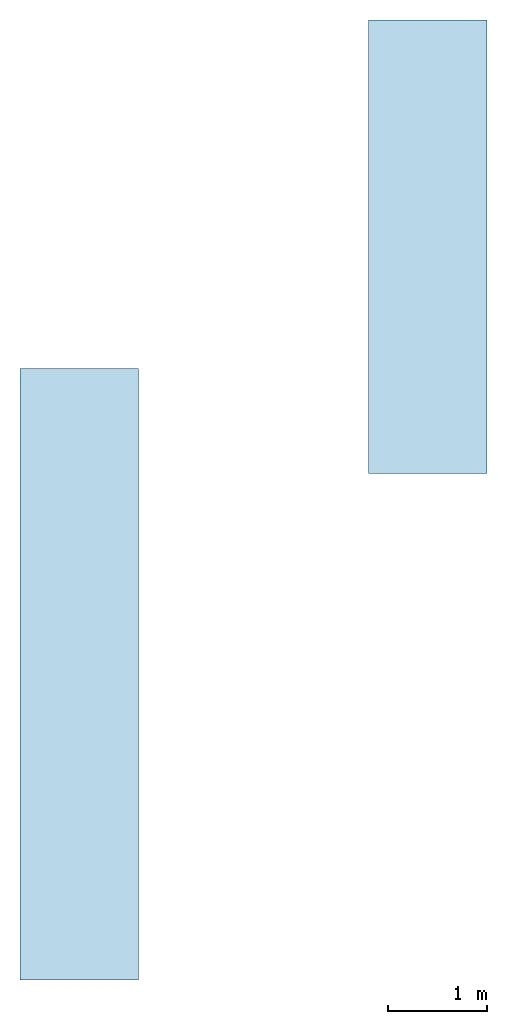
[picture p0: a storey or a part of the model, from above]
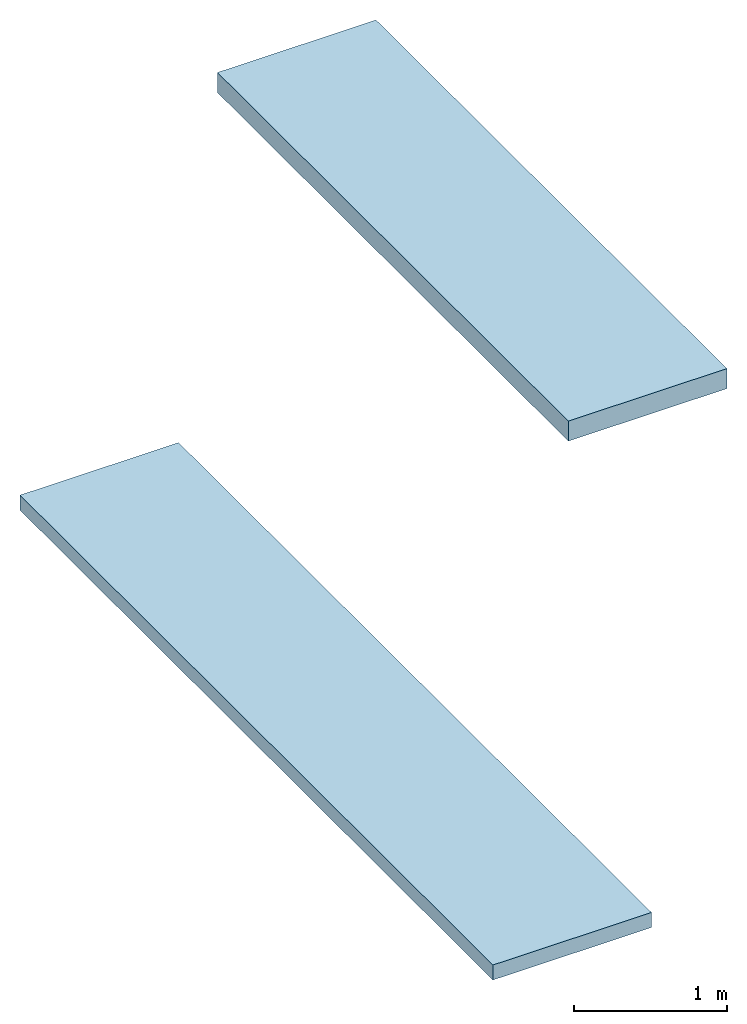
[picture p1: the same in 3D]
Properties of the parts of a building model (IFC2X3)

# File
Description: ViewDefinition [CoordinationView]
Time: 2023-01-18T09:51:32
Written by: The EXPRESS Data Manager Version 5.02.0100.07 : 28 Aug 2013
Made in: 21.1.70.21 - Exporter 21.1.70.21 - Alternate UI 21.1.70.21
Comment: STEP Physical File produced by: The EXPRESS Data Manager Version 5.02.0100.07 : 28 Aug 2013 * Module: EDMstepFileFactory/EDMstandAlone * Creation date: Wed Jan 18 09:51:32 2023 * Host: BIM-LT03 * Database: C:\Users\DONNEE~1\AppData\Local\Temp\6dfd9f73-01cb-4fe2-bb7c-203e315a706e\c1fa6ac3-a54c-4e9e-a12f-ee402be6c916\ifc * Database version: 5507 * Database creation date: Wed Jan 18 09:51:32 2023 * Schema: IFC2X3 * Model: DataRepository.ifc * Model creation date: Wed Jan 18 09:51:32 2023 * Header model: DataRepository.ifc_HeaderModel * Header model creation date: Wed Jan 18 09:51:32 2023 * EDMuser: sdai-user * EDMgroup: sdai-group * License ID and type: 5605 : Permanent license. Expiry date: * EDMstepFileFactory options: 020000

# IfcSite, Default
RefLatitude: 42, 24, 53, 508911; RefLongitude: -71, -15, -29, -58837; RefElevation: 0 mm
Pset_ProductRequirements - Category: Project Information

# IfcBuilding
Pset_BuildingCommon - NumberOfStoreys: 1
Pset_ProductRequirements - Category: Project Information

# IfcBuildingStorey: Level:Level 1, Begane grond
LongName: Begane grond; Elevation: 0 mm
Pset_AirSideSystemInformation - Name: Begane grond
Pset_ProductRequirements - Name: Begane grond; Category: Levels

# IfcSlab: Floor:NLRS_23_FL_Multifit 035_120x1200x6200mm, Floor:NLRS_23_FL_Multifit 035_120x1200x6200mm:2494
In: Begane grond
Type - PredefinedType: FLOOR; Material: Knauf Insulation_Multifit 035 Ecose® glaswol 120 mm
Type - Pset_ElementShading - Roughness: 304.8 mm
Type - Pset_ManufacturerTypeInformation - Manufacturer: Knauf Insulation B.V.
Type - Pset_ProductRequirements - Category: Floors
Type - Pset_QuantityTakeOff - Reference: Floor:NLRS_23_FL_Multifit 035_120x1200x6200mm
Type - Pset_ReinforcementBarPitchOfSlab - Description: Multifit - 120mm; Reference: Floor:NLRS_23_FL_Multifit 035_120x1200x6200mm
Type - Pset_SlabCommon - Reference: Floor:NLRS_23_FL_Multifit 035_120x1200x6200mm; IsExternal: no; ThermalTransmittance: 0.291667 kg/K/s3
Type - Pset_Floor Schedule Multifit 035 LOD200 - Assembly Code: 23; Type Image: Raster image: Multifit 035.jpg (2); Model: Multifit 035 is een onbeklede glaswolplaat met ECOSE® Technology.; Manufacturer: Knauf Insulation B.V.; URL: www.knaufinsulation.nl; Description: Multifit - 120mm
Classification: 23 Vloeren (Uniformat)
Pset_SlabCommon - LoadBearing: no; PitchAngle: 0 deg
Pset_Floor Schedule Multifit 035 LOD200 - Type: Floor: NLRS_23_FL_Multifit 035_120x1200x6200mm

# IfcSlab: Floor:NLRS_23_FL_Multifit 035_160x1200x4600mm, Floor:NLRS_23_FL_Multifit 035_160x1200x4600mm:3665
In: Begane grond
Type - PredefinedType: FLOOR; Material: Knauf Insulation_Multifit 035 Ecose® glaswol 160 mm
Type - Pset_ElementShading - Roughness: 304.8 mm
Type - Pset_ManufacturerTypeInformation - Manufacturer: Knauf Insulation B.V.
Type - Pset_ProductRequirements - Category: Floors
Type - Pset_QuantityTakeOff - Reference: Floor:NLRS_23_FL_Multifit 035_160x1200x4600mm
Type - Pset_ReinforcementBarPitchOfSlab - Description: Multifit - 160mm; Reference: Floor:NLRS_23_FL_Multifit 035_160x1200x4600mm
Type - Pset_SlabCommon - IsExternal: no; Reference: Floor:NLRS_23_FL_Multifit 035_160x1200x4600mm; ThermalTransmittance: 0.21875 kg/K/s3
Type - Pset_Floor Schedule Multifit 035 LOD200 - Assembly Code: 23; Type Image: Raster image: Multifit 035.jpg (2); Model: Multifit 035 is een onbeklede glaswolplaat met ECOSE® Technology.; Manufacturer: Knauf Insulation B.V.; URL: www.knaufinsulation.nl; Description: Multifit - 160mm
Classification: 23 Vloeren (Uniformat)
Pset_SlabCommon - LoadBearing: no; PitchAngle: 0 deg
Pset_Floor Schedule Multifit 035 LOD200 - Type: Floor: NLRS_23_FL_Multifit 035_160x1200x4600mm
